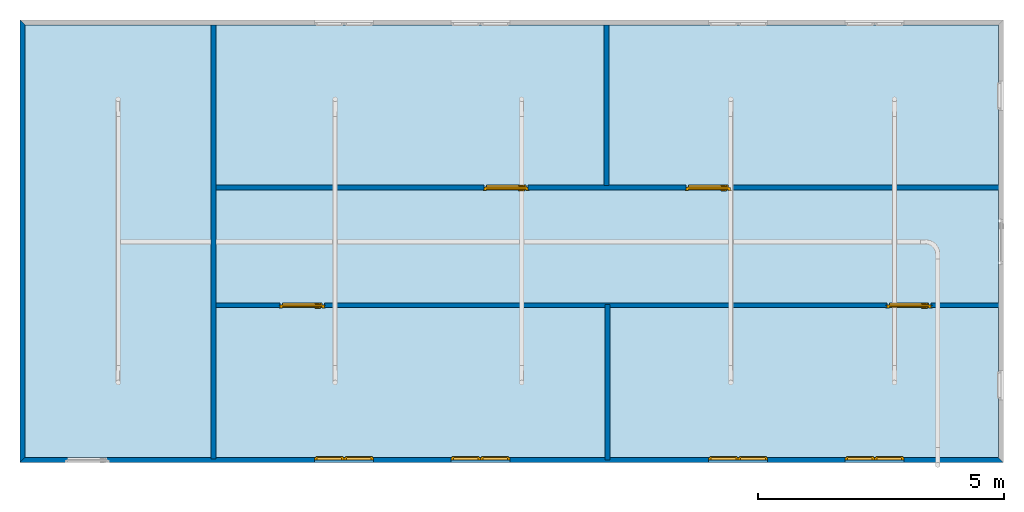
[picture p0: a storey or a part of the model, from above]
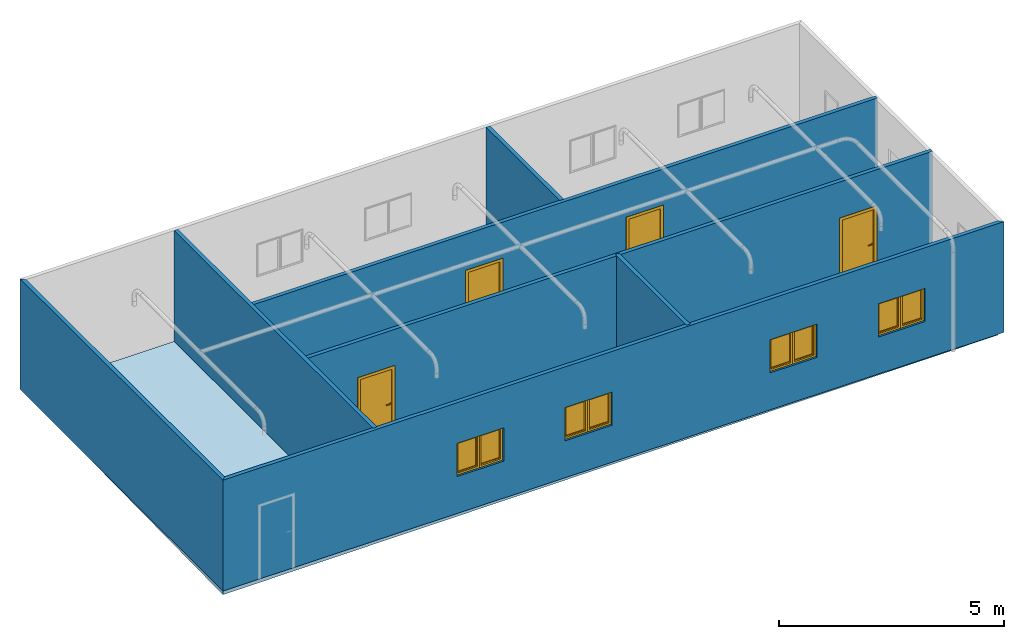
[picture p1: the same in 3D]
Properties of the parts of a building model (IFC4)

# File
Description: ViewDefinition[DesignTransferView]
File name: s09-activity.ifc
Time: 2026-11-02T20:52:51+08:00
Written by: IfcOpenShell 0.8.5-post1
Made in: Bonsai 0.8.5-post1
Authorization: Nobody

# IfcDistributionPort (62)
PredefinedType: PIPE

# IfcDoor: Unnamed (6)
In: GF
Type - PredefinedType: DOOR; OperationType: SINGLE_SWING_LEFT
Type - BBIM_Door - Data: {"door_type": "SINGLE_SWING_LEFT", "overall_height": 2.0, "overall_width": 0.8999999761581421, "lining_properties": {"lining_depth": 0.05000000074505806, "lining_thickness": 0.05000000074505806, "lining_offset": 0.0, "lining_to_panel_offset_x": 0.02500000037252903, "lining_to_panel_offset_y": 0.02500000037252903, "transom_thickness": 0.0, "casing_thickness": 0.07500000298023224, "casing_depth": 0.004999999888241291, "threshold_thickness": 0.02500000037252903, "threshold_depth": 0.10000000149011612, "threshold_offset": 0.0}, "panel_properties": {"panel_depth": 0.03500000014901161, "panel_width_ratio": 1.0}}
OverallHeight: 2 m; OverallWidth: 0.9 m

# IfcOpeningElement (35)
In: GF
PredefinedType: OPENING
Name
23 x Opening
12 x Unnamed

# IfcPipeFitting: Bend (12)
In: GF
Type - PredefinedType: BEND
Type - BBIM_Fitting - Data: {"start_length": 0.10000000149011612, "end_length": 0.10000000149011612, "radius": 0.20000000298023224, "angle": 89.99999749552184, "lateral_axis": 1, "lateral_sign": -1.0, "z_axis_sign": 1, "main_profile_dimension": 0.05}

# IfcPipeSegment: Unnamed (18)
In: GF
Type - PredefinedType: RIGIDSEGMENT; Material: Unknown
EPset_Parametric - Engine: Bonsai.DumbProfile

# IfcSlab: Unnamed, Slab
In: GF
Type - PredefinedType: FLOOR; Material: Unknown 0.1 m
Type - EPset_Parametric - LayerSetDirection: AXIS3
EPset_Parametric - Engine: Bonsai.DumbLayer3

# IfcWall: Unnamed (9)
In: GF
Type - PredefinedType: SOLIDWALL; Material: Unknown 0.1 m
Type - EPset_Parametric - LayerSetDirection: AXIS2
EPset_Parametric - Engine: Bonsai.DumbLayer2

# IfcWindow: Unnamed (18)
In: GF
Type - PredefinedType: WINDOW; PartitioningType: SINGLE_PANEL
Type - BBIM_Window - Data: {"window_type": "SINGLE_PANEL", "overall_height": 0.8999999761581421, "overall_width": 0.6000000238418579, "lining_properties": {"lining_depth": 0.05000000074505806, "lining_thickness": 0.05000000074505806, "lining_offset": 0.05000000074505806, "lining_to_panel_offset_x": 0.02500000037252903, "lining_to_panel_offset_y": 0.02500000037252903}, "panel_properties": {"frame_depth": [0.03500000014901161, 0.03500000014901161, 0.03500000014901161], "frame_thickness": [0.03500000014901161, 0.03500000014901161, 0.03500000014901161]}}
OverallHeight: 0.9 m; OverallWidth: 0.6 m
Name
16 x Window
Window.004
Window.005
